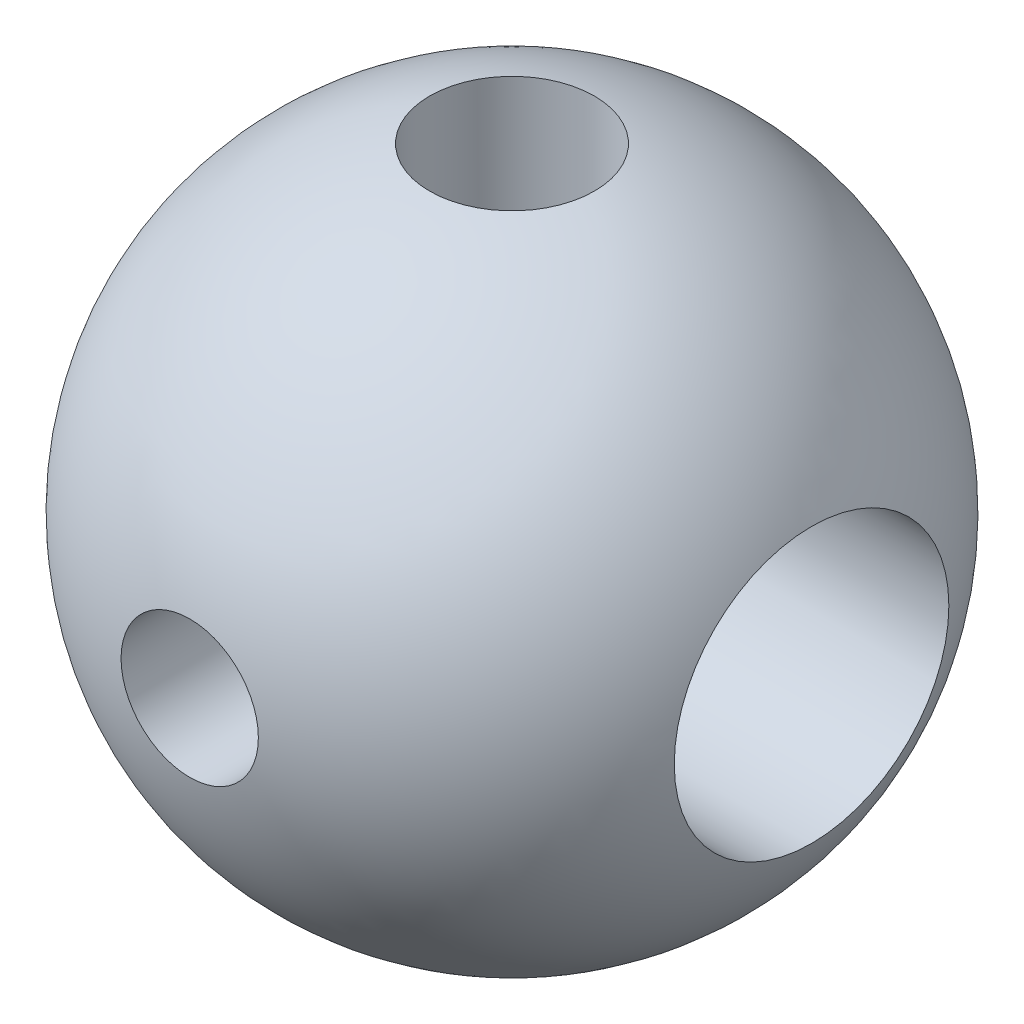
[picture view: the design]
ISO-10303-21;
HEADER;
FILE_DESCRIPTION(('STEP AP214'),'2;1');
FILE_NAME('part.step','',(''),(''),'','','');
FILE_SCHEMA(('AUTOMOTIVE_DESIGN { 1 0 10303 214 1 1 1 1 }'));
ENDSEC;
DATA;
#1=APPLICATION_CONTEXT('core data for automotive mechanical design processes');
#2=APPLICATION_PROTOCOL_DEFINITION('international standard','automotive_design',2000,#1);
#3=PRODUCT_CONTEXT('',#1,'mechanical');
#4=PRODUCT('Part','Part','',(#3));
#5=PRODUCT_RELATED_PRODUCT_CATEGORY('part','',(#4));
#6=PRODUCT_DEFINITION_FORMATION('','',#4);
#7=PRODUCT_DEFINITION_CONTEXT('part definition',#1,'design');
#8=PRODUCT_DEFINITION('design','',#6,#7);
#9=PRODUCT_DEFINITION_SHAPE('','',#8);
#10=(LENGTH_UNIT() NAMED_UNIT(*) SI_UNIT(.MILLI.,.METRE.));
#11=(NAMED_UNIT(*) PLANE_ANGLE_UNIT() SI_UNIT($,.RADIAN.));
#12=(NAMED_UNIT(*) SI_UNIT($,.STERADIAN.) SOLID_ANGLE_UNIT());
#13=UNCERTAINTY_MEASURE_WITH_UNIT(LENGTH_MEASURE(1.E-05),#10,'distance_accuracy_value','');
#14=(GEOMETRIC_REPRESENTATION_CONTEXT(3) GLOBAL_UNCERTAINTY_ASSIGNED_CONTEXT((#13)) GLOBAL_UNIT_ASSIGNED_CONTEXT((#10,
#11,#12)) REPRESENTATION_CONTEXT('',''));
#15=CARTESIAN_POINT('',(0.,0.,0.));
#16=DIRECTION('',(0.,0.,1.));
#17=DIRECTION('',(1.,0.,0.));
#18=AXIS2_PLACEMENT_3D('',#15,#16,#17);
#19=CARTESIAN_POINT('',(0.,-48.,0.));
#20=DIRECTION('',(0.,1.,0.));
#21=DIRECTION('',(0.,0.,1.));
#22=AXIS2_PLACEMENT_3D('',#19,#20,#21);
#23=CYLINDRICAL_SURFACE('',#22,12.);
#24=CARTESIAN_POINT('',(0.,-16.,12.));
#25=CARTESIAN_POINT('',(0.301908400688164,-15.9999971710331,12.0000019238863));
#26=CARTESIAN_POINT('',(0.603795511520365,-16.0085762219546,11.9885900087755));
#27=CARTESIAN_POINT('',(1.20488924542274,-16.0424977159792,11.9431600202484));
#28=CARTESIAN_POINT('',(1.50409604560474,-16.0678390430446,11.9091434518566));
#29=CARTESIAN_POINT('',(2.09765466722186,-16.1342200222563,11.8190547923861));
#30=CARTESIAN_POINT('',(2.39200179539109,-16.1752740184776,11.7629625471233));
#31=CARTESIAN_POINT('',(2.97349307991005,-16.2714289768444,11.6295889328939));
#32=CARTESIAN_POINT('',(3.26063685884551,-16.3265306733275,11.5523064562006));
#33=CARTESIAN_POINT('',(3.82391010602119,-16.4483194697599,11.3782233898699));
#34=CARTESIAN_POINT('',(4.10010631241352,-16.5149160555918,11.2815744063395));
#35=CARTESIAN_POINT('',(4.64262215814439,-16.6578936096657,11.069369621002));
#36=CARTESIAN_POINT('',(4.90893780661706,-16.7342784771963,10.9538062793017));
#37=CARTESIAN_POINT('',(5.43063769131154,-16.8946796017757,10.7047527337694));
#38=CARTESIAN_POINT('',(5.68602189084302,-16.9786958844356,10.5712624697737));
#39=CARTESIAN_POINT('',(6.18509809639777,-17.1522796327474,10.2872252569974));
#40=CARTESIAN_POINT('',(6.42879086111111,-17.2418467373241,10.1366794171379));
#41=CARTESIAN_POINT('',(6.93296744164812,-17.4357521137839,9.79983575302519));
#42=CARTESIAN_POINT('',(7.19185705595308,-17.5405567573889,9.61141728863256));
#43=CARTESIAN_POINT('',(7.6933159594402,-17.7520540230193,9.21493722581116));
#44=CARTESIAN_POINT('',(7.93588414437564,-17.8587467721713,9.00687430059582));
#45=CARTESIAN_POINT('',(8.40402030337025,-18.0716369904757,8.57173550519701));
#46=CARTESIAN_POINT('',(8.62957276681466,-18.1778339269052,8.34464267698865));
#47=CARTESIAN_POINT('',(9.06235556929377,-18.3872358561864,7.87249861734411));
#48=CARTESIAN_POINT('',(9.26959217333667,-18.4904418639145,7.62745357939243));
#49=CARTESIAN_POINT('',(9.68614025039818,-18.7025608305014,7.092648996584));
#50=CARTESIAN_POINT('',(9.89323949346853,-18.8108789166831,6.80092220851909));
#51=CARTESIAN_POINT('',(10.2818845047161,-19.0181526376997,6.19770739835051));
#52=CARTESIAN_POINT('',(10.4634279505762,-19.1171074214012,5.88621758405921));
#53=CARTESIAN_POINT('',(10.7988768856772,-19.3027521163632,5.24546661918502));
#54=CARTESIAN_POINT('',(10.9528016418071,-19.3894505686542,4.91621806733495));
#55=CARTESIAN_POINT('',(11.2311195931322,-19.5480167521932,4.242037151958));
#56=CARTESIAN_POINT('',(11.3555176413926,-19.6198869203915,3.89710737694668));
#57=CARTESIAN_POINT('',(11.5624812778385,-19.7404306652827,3.22795776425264));
#58=CARTESIAN_POINT('',(11.6479057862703,-19.7906632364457,2.9049021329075));
#59=CARTESIAN_POINT('',(11.7917710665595,-19.8756757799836,2.25082759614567));
#60=CARTESIAN_POINT('',(11.8502134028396,-19.9104566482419,1.91980915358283));
#61=CARTESIAN_POINT('',(11.9391406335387,-19.9635118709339,1.25298686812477));
#62=CARTESIAN_POINT('',(11.9696474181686,-19.9817991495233,0.91718698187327));
#63=CARTESIAN_POINT('',(12.0022585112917,-20.0013507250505,0.243729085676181));
#64=CARTESIAN_POINT('',(12.0043657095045,-20.0026167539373,-0.0939287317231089));
#65=CARTESIAN_POINT('',(11.9816620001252,-19.9890013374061,-0.725958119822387));
#66=CARTESIAN_POINT('',(11.9601608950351,-19.9761053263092,-1.02049867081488));
#67=CARTESIAN_POINT('',(11.8956497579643,-19.9375477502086,-1.60634317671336));
#68=CARTESIAN_POINT('',(11.8526419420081,-19.9118875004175,-1.89764746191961));
#69=CARTESIAN_POINT('',(11.7456574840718,-19.848390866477,-2.47502497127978));
#70=CARTESIAN_POINT('',(11.681680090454,-19.8105540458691,-2.76109800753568));
#71=CARTESIAN_POINT('',(11.5335067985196,-19.7235439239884,-3.32619184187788));
#72=CARTESIAN_POINT('',(11.449310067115,-19.6743701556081,-3.60521234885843));
#73=CARTESIAN_POINT('',(11.2610805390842,-19.5654290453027,-4.15611235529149));
#74=CARTESIAN_POINT('',(11.1569409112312,-19.5056047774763,-4.42794398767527));
#75=CARTESIAN_POINT('',(10.9300876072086,-19.3767412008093,-4.96158056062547));
#76=CARTESIAN_POINT('',(10.8073673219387,-19.307698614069,-5.22338189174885));
#77=CARTESIAN_POINT('',(10.5444249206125,-19.1617572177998,-5.73567682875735));
#78=CARTESIAN_POINT('',(10.4042061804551,-19.0848599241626,-5.98617260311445));
#79=CARTESIAN_POINT('',(10.1071922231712,-18.9245792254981,-6.47506872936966));
#80=CARTESIAN_POINT('',(9.9503910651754,-18.8411934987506,-6.71346470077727));
#81=CARTESIAN_POINT('',(9.60153051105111,-18.6591712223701,-7.2049947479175));
#82=CARTESIAN_POINT('',(9.40749645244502,-18.5599019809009,-7.45649461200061));
#83=CARTESIAN_POINT('',(9.00104402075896,-18.3572263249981,-7.94238968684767));
#84=CARTESIAN_POINT('',(8.788624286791,-18.253819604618,-8.17678362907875));
#85=CARTESIAN_POINT('',(8.34612135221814,-18.0449339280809,-8.62799224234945));
#86=CARTESIAN_POINT('',(8.11601317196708,-17.939452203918,-8.84478112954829));
#87=CARTESIAN_POINT('',(7.63939133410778,-17.7289199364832,-9.25956168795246));
#88=CARTESIAN_POINT('',(7.39288234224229,-17.6238692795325,-9.45755866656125));
#89=CARTESIAN_POINT('',(6.85463170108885,-17.404560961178,-9.85590025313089));
#90=CARTESIAN_POINT('',(6.56096287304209,-17.290652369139,-10.053842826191));
#91=CARTESIAN_POINT('',(5.95522167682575,-17.0700064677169,-10.4240751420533));
#92=CARTESIAN_POINT('',(5.64314629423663,-16.9632703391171,-10.5963606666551));
#93=CARTESIAN_POINT('',(5.00243922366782,-16.7610308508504,-10.913439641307));
#94=CARTESIAN_POINT('',(4.67383329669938,-16.6655107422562,-11.0582742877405));
#95=CARTESIAN_POINT('',(4.00145187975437,-16.4895880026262,-11.3189334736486));
#96=CARTESIAN_POINT('',(3.65768241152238,-16.409179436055,-11.4347694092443));
#97=CARTESIAN_POINT('',(3.04421360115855,-16.2849826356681,-11.610679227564));
#98=CARTESIAN_POINT('',(2.77725775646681,-16.2370569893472,-11.6774582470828));
#99=CARTESIAN_POINT('',(2.23756206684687,-16.1535036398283,-11.7927693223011));
#100=CARTESIAN_POINT('',(1.96482351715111,-16.117873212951,-11.8413054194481));
#101=CARTESIAN_POINT('',(1.41548658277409,-16.0601704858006,-11.9194501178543));
#102=CARTESIAN_POINT('',(1.13889216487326,-16.0380851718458,-11.9490768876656));
#103=CARTESIAN_POINT('',(0.583526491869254,-16.0082363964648,-11.9890365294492));
#104=CARTESIAN_POINT('',(0.304755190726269,-16.0004732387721,-11.9993689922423));
#105=CARTESIAN_POINT('',(-0.253237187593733,-15.9995682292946,-12.0005757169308));
#106=CARTESIAN_POINT('',(-0.532458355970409,-16.0064465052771,-11.9914231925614));
#107=CARTESIAN_POINT('',(-1.08885114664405,-16.0345997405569,-11.9537507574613));
#108=CARTESIAN_POINT('',(-1.36602275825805,-16.0558747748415,-11.9252307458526));
#109=CARTESIAN_POINT('',(-1.91652811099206,-16.1120462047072,-11.8492273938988));
#110=CARTESIAN_POINT('',(-2.18985914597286,-16.1469517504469,-11.8017313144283));
#111=CARTESIAN_POINT('',(-2.73078140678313,-16.229161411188,-11.6884218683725));
#112=CARTESIAN_POINT('',(-2.9983724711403,-16.2764658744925,-11.6226079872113));
#113=CARTESIAN_POINT('',(-3.52598231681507,-16.3818746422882,-11.4735560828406));
#114=CARTESIAN_POINT('',(-3.78601230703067,-16.4399619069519,-11.3903455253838));
#115=CARTESIAN_POINT('',(-4.29791560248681,-16.5653390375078,-11.2072231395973));
#116=CARTESIAN_POINT('',(-4.54978620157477,-16.6326319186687,-11.1073058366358));
#117=CARTESIAN_POINT('',(-5.04444759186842,-16.7746924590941,-10.8915731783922));
#118=CARTESIAN_POINT('',(-5.2872377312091,-16.8494606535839,-10.775756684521));
#119=CARTESIAN_POINT('',(-5.76305724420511,-17.0047712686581,-10.5289606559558));
#120=CARTESIAN_POINT('',(-5.99608608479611,-17.0853140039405,-10.3979802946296));
#121=CARTESIAN_POINT('',(-6.49298270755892,-17.2654555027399,-10.0965427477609));
#122=CARTESIAN_POINT('',(-6.75482499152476,-17.3658698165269,-9.92322733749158));
#123=CARTESIAN_POINT('',(-7.26327586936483,-17.5698876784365,-9.55734884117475));
#124=CARTESIAN_POINT('',(-7.50988693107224,-17.6734907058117,-9.36478888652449));
#125=CARTESIAN_POINT('',(-7.98738394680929,-17.8816130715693,-8.9610015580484));
#126=CARTESIAN_POINT('',(-8.21825388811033,-17.986133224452,-8.7497556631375));
#127=CARTESIAN_POINT('',(-8.66313204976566,-18.193711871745,-8.30951773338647));
#128=CARTESIAN_POINT('',(-8.8771393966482,-18.296770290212,-8.08052478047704));
#129=CARTESIAN_POINT('',(-9.31404007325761,-18.5124468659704,-7.57459119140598));
#130=CARTESIAN_POINT('',(-9.53446002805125,-18.6245617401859,-7.29529028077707));
#131=CARTESIAN_POINT('',(-9.95088052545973,-18.8411358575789,-6.71618728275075));
#132=CARTESIAN_POINT('',(-10.1468785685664,-18.9455943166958,-6.41638310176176));
#133=CARTESIAN_POINT('',(-10.512504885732,-19.1439071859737,-5.79794763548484));
#134=CARTESIAN_POINT('',(-10.6821457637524,-19.2377666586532,-5.47932545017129));
#135=CARTESIAN_POINT('',(-10.993163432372,-19.4121884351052,-4.82508968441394));
#136=CARTESIAN_POINT('',(-11.1345440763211,-19.4927525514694,-4.48947842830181));
#137=CARTESIAN_POINT('',(-11.3778836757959,-19.6328061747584,-3.82865235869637));
#138=CARTESIAN_POINT('',(-11.4819596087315,-19.6934011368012,-3.50445198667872));
#139=CARTESIAN_POINT('',(-11.6626203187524,-19.7992764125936,-2.84601413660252));
#140=CARTESIAN_POINT('',(-11.7392061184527,-19.8445572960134,-2.51177703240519));
#141=CARTESIAN_POINT('',(-11.8636029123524,-19.9183977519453,-1.83648767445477));
#142=CARTESIAN_POINT('',(-11.911441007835,-19.946973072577,-1.49544215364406));
#143=CARTESIAN_POINT('',(-11.9776197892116,-19.9865620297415,-0.809503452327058));
#144=CARTESIAN_POINT('',(-11.9959643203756,-19.9975779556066,-0.464610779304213));
#145=CARTESIAN_POINT('',(-12.0023854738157,-20.001431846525,0.179455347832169));
#146=CARTESIAN_POINT('',(-11.9941753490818,-19.9964998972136,0.478586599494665));
#147=CARTESIAN_POINT('',(-11.95549677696,-19.9733236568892,1.07486280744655));
#148=CARTESIAN_POINT('',(-11.9250307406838,-19.9550808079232,1.37200797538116));
#149=CARTESIAN_POINT('',(-11.8422465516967,-19.9057203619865,1.96213810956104));
#150=CARTESIAN_POINT('',(-11.7899285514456,-19.8746028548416,2.25512310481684));
#151=CARTESIAN_POINT('',(-11.6640981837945,-19.8002174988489,2.83492894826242));
#152=CARTESIAN_POINT('',(-11.5905851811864,-19.756949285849,3.12174961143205));
#153=CARTESIAN_POINT('',(-11.4245704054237,-19.660018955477,3.68285438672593));
#154=CARTESIAN_POINT('',(-11.3323940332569,-19.6065357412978,3.95726608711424));
#155=CARTESIAN_POINT('',(-11.1292862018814,-19.4898461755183,4.4968998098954));
#156=CARTESIAN_POINT('',(-11.0183552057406,-19.4266400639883,4.76212205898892));
#157=CARTESIAN_POINT('',(-10.7787258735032,-19.291737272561,5.2821427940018));
#158=CARTESIAN_POINT('',(-10.6500282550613,-19.2200409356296,5.53694170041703));
#159=CARTESIAN_POINT('',(-10.3758015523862,-19.0694552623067,6.03520075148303));
#160=CARTESIAN_POINT('',(-10.2302663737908,-18.9905633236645,6.27865674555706));
#161=CARTESIAN_POINT('',(-9.90673029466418,-18.8181451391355,6.77899616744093));
#162=CARTESIAN_POINT('',(-9.72692044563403,-18.7239589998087,7.03448334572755));
#163=CARTESIAN_POINT('',(-9.348935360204,-18.5304135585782,7.52957259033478));
#164=CARTESIAN_POINT('',(-9.15075189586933,-18.4310519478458,7.76916745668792));
#165=CARTESIAN_POINT('',(-8.7369667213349,-18.2291509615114,8.23175510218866));
#166=CARTESIAN_POINT('',(-8.52135096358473,-18.1266090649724,8.45473420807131));
#167=CARTESIAN_POINT('',(-8.07376590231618,-17.9205531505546,8.88314617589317));
#168=CARTESIAN_POINT('',(-7.84179571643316,-17.8170390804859,9.08857808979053));
#169=CARTESIAN_POINT('',(-7.33186369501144,-17.5982003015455,9.50608800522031));
#170=CARTESIAN_POINT('',(-7.05180187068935,-17.4830446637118,9.71569839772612));
#171=CARTESIAN_POINT('',(-6.47302014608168,-17.2577211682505,10.110526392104));
#172=CARTESIAN_POINT('',(-6.17429798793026,-17.1475539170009,10.2957410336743));
#173=CARTESIAN_POINT('',(-5.55945257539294,-16.9358863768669,10.6403306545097));
#174=CARTESIAN_POINT('',(-5.24333396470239,-16.8343837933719,10.7997124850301));
#175=CARTESIAN_POINT('',(-4.59511438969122,-16.6438937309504,11.0910374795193));
#176=CARTESIAN_POINT('',(-4.26301779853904,-16.5549028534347,11.2229880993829));
#177=CARTESIAN_POINT('',(-3.61366723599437,-16.4002389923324,11.4476706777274));
#178=CARTESIAN_POINT('',(-3.29755988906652,-16.3332252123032,11.5427864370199));
#179=CARTESIAN_POINT('',(-2.6556392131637,-16.2158236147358,11.7071473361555));
#180=CARTESIAN_POINT('',(-2.32982667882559,-16.1654344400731,11.7763945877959));
#181=CARTESIAN_POINT('',(-1.67181932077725,-16.0838007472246,11.8876462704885));
#182=CARTESIAN_POINT('',(-1.33963755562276,-16.0525206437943,11.929701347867));
#183=CARTESIAN_POINT('',(-0.671628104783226,-16.0106231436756,11.9858753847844));
#184=CARTESIAN_POINT('',(-0.335800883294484,-16.000003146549,11.9999978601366));
#185=CARTESIAN_POINT('',(0.,-16.,12.));
#186=B_SPLINE_CURVE_WITH_KNOTS('',3,(#24,#25,#26,#27,#28,#29,#30,#31,#32,#33,#34,#35,#36,#37,
#38,#39,#40,#41,#42,#43,#44,#45,#46,#47,#48,#49,#50,#51,#52,#53,#54,#55,#56,#57,#58,#59,#60,#61,
#62,#63,#64,#65,#66,#67,#68,#69,#70,#71,#72,#73,#74,#75,#76,#77,#78,#79,#80,#81,#82,#83,#84,#85,
#86,#87,#88,#89,#90,#91,#92,#93,#94,#95,#96,#97,#98,#99,#100,#101,#102,#103,#104,#105,#106,#107,
#108,#109,#110,#111,#112,#113,#114,#115,#116,#117,#118,#119,#120,#121,#122,#123,#124,#125,#126,
#127,#128,#129,#130,#131,#132,#133,#134,#135,#136,#137,#138,#139,#140,#141,#142,#143,#144,#145,
#146,#147,#148,#149,#150,#151,#152,#153,#154,#155,#156,#157,#158,#159,#160,#161,#162,#163,#164,
#165,#166,#167,#168,#169,#170,#171,#172,#173,#174,#175,#176,#177,#178,#179,#180,#181,#182,#183,
#184,#185),.UNSPECIFIED.,.T.,.F.,(4,2,2,2,2,2,2,2,2,2,2,2,2,2,2,2,2,2,2,2,2,2,2,2,2,2,2,2,2,2,2,
2,2,2,2,2,2,2,2,2,2,2,2,2,2,2,2,2,2,2,2,2,2,2,2,2,2,2,2,2,2,2,2,2,2,2,2,2,2,2,2,2,2,2,2,2,2,2,2,
2,4),(0.,0.905356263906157,1.81065225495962,2.71677666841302,3.62294845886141,4.5222857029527,
5.42198232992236,6.32168197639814,7.22132315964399,8.23104850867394,9.24084210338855,
10.2515453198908,11.2619014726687,12.3818273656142,13.5018549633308,14.6210981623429,
15.7401572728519,16.7524414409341,17.7646669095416,18.7760985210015,19.7874272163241,
20.673184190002,21.5588499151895,22.4445473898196,23.3302813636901,24.2208999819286,
25.1118361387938,26.0026006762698,26.8936854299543,27.8910660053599,28.8885204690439,
29.8874103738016,30.8860173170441,32.0006941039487,33.1155539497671,34.2287272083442,
35.3414623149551,36.1785892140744,37.0155305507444,37.8516665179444,38.6878202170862,
39.5251241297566,40.3624324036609,41.2003037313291,42.0381985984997,42.8747804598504,
43.7116369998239,44.5485535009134,45.3855156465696,46.3735461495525,47.3614161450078,
48.3502765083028,49.3391880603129,50.456908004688,51.5747422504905,52.6920402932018,
53.8091858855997,54.8452180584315,55.881211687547,56.9162271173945,57.9511075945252,
58.8478548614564,59.7445049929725,60.6411488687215,61.5378196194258,62.4200276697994,
63.3022139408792,64.1843645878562,65.0668355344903,66.044765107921,67.0231347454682,
68.002300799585,68.9815197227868,70.0850618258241,71.1887377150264,72.2921204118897,
73.3952028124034,74.4042890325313,75.413292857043,76.4204119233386,77.427404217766),.UNSPECIFIED.);
#187=CARTESIAN_POINT('',(0.,-16.,12.));
#188=VERTEX_POINT('',#187);
#189=EDGE_CURVE('E62',#188,#188,#186,.T.);
#190=ORIENTED_EDGE('',*,*,#189,.T.);
#191=EDGE_LOOP('',(#190));
#192=FACE_BOUND('',#191,.T.);
#193=CARTESIAN_POINT('',(0.,-46.475800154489,0.));
#194=DIRECTION('',(0.,1.,0.));
#195=DIRECTION('',(0.,0.,1.));
#196=AXIS2_PLACEMENT_3D('',#193,#194,#195);
#197=CIRCLE('',#196,12.);
#198=CARTESIAN_POINT('',(0.,-46.475800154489,12.));
#199=VERTEX_POINT('',#198);
#200=EDGE_CURVE('E48',#199,#199,#197,.F.);
#201=ORIENTED_EDGE('',*,*,#200,.T.);
#202=EDGE_LOOP('',(#201));
#203=FACE_BOUND('',#202,.T.);
#204=ADVANCED_FACE('F36',(#192,#203),#23,.F.);
#205=CARTESIAN_POINT('',(0.,0.,0.));
#206=DIRECTION('',(0.,1.,0.));
#207=DIRECTION('',(1.,0.,0.));
#208=AXIS2_PLACEMENT_3D('',#205,#206,#207);
#209=SPHERICAL_SURFACE('',#208,48.);
#210=CARTESIAN_POINT('',(0.,0.,46.946778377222));
#211=DIRECTION('',(0.,0.,-1.));
#212=DIRECTION('',(-1.,0.,0.));
#213=AXIS2_PLACEMENT_3D('',#210,#211,#212);
#214=CIRCLE('',#213,10.);
#215=CARTESIAN_POINT('',(-10.,0.,46.946778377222));
#216=VERTEX_POINT('',#215);
#217=EDGE_CURVE('E63',#216,#216,#214,.F.);
#218=ORIENTED_EDGE('',*,*,#217,.F.);
#219=EDGE_LOOP('',(#218));
#220=FACE_BOUND('',#219,.T.);
#221=CARTESIAN_POINT('',(0.,0.,-46.946778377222));
#222=DIRECTION('',(0.,0.,1.));
#223=DIRECTION('',(1.,0.,0.));
#224=AXIS2_PLACEMENT_3D('',#221,#222,#223);
#225=CIRCLE('',#224,10.);
#226=CARTESIAN_POINT('',(10.,0.,-46.946778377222));
#227=VERTEX_POINT('',#226);
#228=EDGE_CURVE('E85',#227,#227,#225,.F.);
#229=ORIENTED_EDGE('',*,*,#228,.F.);
#230=EDGE_LOOP('',(#229));
#231=FACE_BOUND('',#230,.T.);
#232=CARTESIAN_POINT('',(43.6348484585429,0.,0.));
#233=DIRECTION('',(-1.,0.,0.));
#234=DIRECTION('',(0.,0.,1.));
#235=AXIS2_PLACEMENT_3D('',#232,#233,#234);
#236=CIRCLE('',#235,20.);
#237=CARTESIAN_POINT('',(43.6348484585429,0.,20.));
#238=VERTEX_POINT('',#237);
#239=EDGE_CURVE('E53',#238,#238,#236,.F.);
#240=ORIENTED_EDGE('',*,*,#239,.F.);
#241=EDGE_LOOP('',(#240));
#242=FACE_BOUND('',#241,.T.);
#243=CARTESIAN_POINT('',(-43.6348484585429,0.,0.));
#244=DIRECTION('',(1.,0.,0.));
#245=DIRECTION('',(0.,0.,-1.));
#246=AXIS2_PLACEMENT_3D('',#243,#244,#245);
#247=CIRCLE('',#246,20.);
#248=CARTESIAN_POINT('',(-43.6348484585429,0.,-20.));
#249=VERTEX_POINT('',#248);
#250=EDGE_CURVE('E94',#249,#249,#247,.F.);
#251=ORIENTED_EDGE('',*,*,#250,.F.);
#252=EDGE_LOOP('',(#251));
#253=FACE_BOUND('',#252,.T.);
#254=CARTESIAN_POINT('',(0.,46.475800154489,0.));
#255=DIRECTION('',(0.,-1.,0.));
#256=DIRECTION('',(0.,0.,-1.));
#257=AXIS2_PLACEMENT_3D('',#254,#255,#256);
#258=CIRCLE('',#257,12.);
#259=CARTESIAN_POINT('',(0.,46.475800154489,-12.));
#260=VERTEX_POINT('',#259);
#261=EDGE_CURVE('E10',#260,#260,#258,.F.);
#262=ORIENTED_EDGE('',*,*,#261,.F.);
#263=EDGE_LOOP('',(#262));
#264=FACE_BOUND('',#263,.T.);
#265=ORIENTED_EDGE('',*,*,#200,.F.);
#266=EDGE_LOOP('',(#265));
#267=FACE_BOUND('',#266,.T.);
#268=ADVANCED_FACE('F38',(#220,#231,#242,#253,#264,#267),#209,.T.);
#269=CARTESIAN_POINT('',(0.,16.,12.));
#270=CARTESIAN_POINT('',(-0.301908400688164,15.9999971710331,12.0000019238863));
#271=CARTESIAN_POINT('',(-0.603795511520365,16.0085762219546,11.9885900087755));
#272=CARTESIAN_POINT('',(-1.20488924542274,16.0424977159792,11.9431600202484));
#273=CARTESIAN_POINT('',(-1.50409604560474,16.0678390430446,11.9091434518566));
#274=CARTESIAN_POINT('',(-2.09765466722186,16.1342200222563,11.8190547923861));
#275=CARTESIAN_POINT('',(-2.39200179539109,16.1752740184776,11.7629625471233));
#276=CARTESIAN_POINT('',(-2.97349307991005,16.2714289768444,11.6295889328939));
#277=CARTESIAN_POINT('',(-3.26063685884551,16.3265306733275,11.5523064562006));
#278=CARTESIAN_POINT('',(-3.82391010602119,16.4483194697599,11.3782233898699));
#279=CARTESIAN_POINT('',(-4.10010631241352,16.5149160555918,11.2815744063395));
#280=CARTESIAN_POINT('',(-4.64262215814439,16.6578936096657,11.069369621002));
#281=CARTESIAN_POINT('',(-4.90893780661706,16.7342784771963,10.9538062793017));
#282=CARTESIAN_POINT('',(-5.43063769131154,16.8946796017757,10.7047527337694));
#283=CARTESIAN_POINT('',(-5.68602189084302,16.9786958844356,10.5712624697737));
#284=CARTESIAN_POINT('',(-6.18509809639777,17.1522796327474,10.2872252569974));
#285=CARTESIAN_POINT('',(-6.42879086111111,17.2418467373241,10.1366794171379));
#286=CARTESIAN_POINT('',(-6.93296744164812,17.4357521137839,9.79983575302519));
#287=CARTESIAN_POINT('',(-7.19185705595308,17.5405567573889,9.61141728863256));
#288=CARTESIAN_POINT('',(-7.6933159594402,17.7520540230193,9.21493722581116));
#289=CARTESIAN_POINT('',(-7.93588414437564,17.8587467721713,9.00687430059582));
#290=CARTESIAN_POINT('',(-8.40402030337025,18.0716369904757,8.57173550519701));
#291=CARTESIAN_POINT('',(-8.62957276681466,18.1778339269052,8.34464267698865));
#292=CARTESIAN_POINT('',(-9.06235556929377,18.3872358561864,7.87249861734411));
#293=CARTESIAN_POINT('',(-9.26959217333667,18.4904418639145,7.62745357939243));
#294=CARTESIAN_POINT('',(-9.68614025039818,18.7025608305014,7.092648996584));
#295=CARTESIAN_POINT('',(-9.89323949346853,18.8108789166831,6.80092220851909));
#296=CARTESIAN_POINT('',(-10.2818845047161,19.0181526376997,6.19770739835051));
#297=CARTESIAN_POINT('',(-10.4634279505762,19.1171074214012,5.88621758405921));
#298=CARTESIAN_POINT('',(-10.7988768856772,19.3027521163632,5.24546661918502));
#299=CARTESIAN_POINT('',(-10.9528016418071,19.3894505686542,4.91621806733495));
#300=CARTESIAN_POINT('',(-11.2311195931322,19.5480167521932,4.242037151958));
#301=CARTESIAN_POINT('',(-11.3555176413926,19.6198869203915,3.89710737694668));
#302=CARTESIAN_POINT('',(-11.5624812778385,19.7404306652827,3.22795776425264));
#303=CARTESIAN_POINT('',(-11.6479057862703,19.7906632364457,2.9049021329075));
#304=CARTESIAN_POINT('',(-11.7917710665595,19.8756757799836,2.25082759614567));
#305=CARTESIAN_POINT('',(-11.8502134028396,19.9104566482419,1.91980915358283));
#306=CARTESIAN_POINT('',(-11.9391406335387,19.9635118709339,1.25298686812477));
#307=CARTESIAN_POINT('',(-11.9696474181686,19.9817991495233,0.91718698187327));
#308=CARTESIAN_POINT('',(-12.0022585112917,20.0013507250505,0.243729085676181));
#309=CARTESIAN_POINT('',(-12.0043657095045,20.0026167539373,-0.0939287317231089));
#310=CARTESIAN_POINT('',(-11.9816620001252,19.9890013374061,-0.725958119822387));
#311=CARTESIAN_POINT('',(-11.9601608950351,19.9761053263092,-1.02049867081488));
#312=CARTESIAN_POINT('',(-11.8956497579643,19.9375477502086,-1.60634317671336));
#313=CARTESIAN_POINT('',(-11.8526419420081,19.9118875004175,-1.89764746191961));
#314=CARTESIAN_POINT('',(-11.7456574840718,19.848390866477,-2.47502497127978));
#315=CARTESIAN_POINT('',(-11.681680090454,19.8105540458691,-2.76109800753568));
#316=CARTESIAN_POINT('',(-11.5335067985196,19.7235439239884,-3.32619184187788));
#317=CARTESIAN_POINT('',(-11.449310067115,19.6743701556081,-3.60521234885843));
#318=CARTESIAN_POINT('',(-11.2610805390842,19.5654290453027,-4.15611235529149));
#319=CARTESIAN_POINT('',(-11.1569409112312,19.5056047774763,-4.42794398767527));
#320=CARTESIAN_POINT('',(-10.9300876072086,19.3767412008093,-4.96158056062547));
#321=CARTESIAN_POINT('',(-10.8073673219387,19.307698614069,-5.22338189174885));
#322=CARTESIAN_POINT('',(-10.5444249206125,19.1617572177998,-5.73567682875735));
#323=CARTESIAN_POINT('',(-10.4042061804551,19.0848599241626,-5.98617260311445));
#324=CARTESIAN_POINT('',(-10.1071922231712,18.9245792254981,-6.47506872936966));
#325=CARTESIAN_POINT('',(-9.9503910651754,18.8411934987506,-6.71346470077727));
#326=CARTESIAN_POINT('',(-9.60153051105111,18.6591712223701,-7.2049947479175));
#327=CARTESIAN_POINT('',(-9.40749645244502,18.5599019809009,-7.45649461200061));
#328=CARTESIAN_POINT('',(-9.00104402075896,18.3572263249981,-7.94238968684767));
#329=CARTESIAN_POINT('',(-8.788624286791,18.253819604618,-8.17678362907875));
#330=CARTESIAN_POINT('',(-8.34612135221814,18.0449339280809,-8.62799224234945));
#331=CARTESIAN_POINT('',(-8.11601317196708,17.939452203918,-8.84478112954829));
#332=CARTESIAN_POINT('',(-7.63939133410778,17.7289199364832,-9.25956168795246));
#333=CARTESIAN_POINT('',(-7.39288234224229,17.6238692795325,-9.45755866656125));
#334=CARTESIAN_POINT('',(-6.85463170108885,17.404560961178,-9.85590025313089));
#335=CARTESIAN_POINT('',(-6.56096287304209,17.290652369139,-10.053842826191));
#336=CARTESIAN_POINT('',(-5.95522167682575,17.0700064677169,-10.4240751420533));
#337=CARTESIAN_POINT('',(-5.64314629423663,16.9632703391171,-10.5963606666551));
#338=CARTESIAN_POINT('',(-5.00243922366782,16.7610308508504,-10.913439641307));
#339=CARTESIAN_POINT('',(-4.67383329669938,16.6655107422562,-11.0582742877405));
#340=CARTESIAN_POINT('',(-4.00145187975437,16.4895880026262,-11.3189334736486));
#341=CARTESIAN_POINT('',(-3.65768241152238,16.409179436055,-11.4347694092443));
#342=CARTESIAN_POINT('',(-3.04421360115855,16.2849826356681,-11.610679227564));
#343=CARTESIAN_POINT('',(-2.77725775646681,16.2370569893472,-11.6774582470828));
#344=CARTESIAN_POINT('',(-2.23756206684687,16.1535036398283,-11.7927693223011));
#345=CARTESIAN_POINT('',(-1.96482351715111,16.117873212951,-11.8413054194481));
#346=CARTESIAN_POINT('',(-1.41548658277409,16.0601704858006,-11.9194501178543));
#347=CARTESIAN_POINT('',(-1.13889216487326,16.0380851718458,-11.9490768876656));
#348=CARTESIAN_POINT('',(-0.583526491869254,16.0082363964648,-11.9890365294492));
#349=CARTESIAN_POINT('',(-0.304755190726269,16.0004732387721,-11.9993689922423));
#350=CARTESIAN_POINT('',(0.253237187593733,15.9995682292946,-12.0005757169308));
#351=CARTESIAN_POINT('',(0.532458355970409,16.0064465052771,-11.9914231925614));
#352=CARTESIAN_POINT('',(1.08885114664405,16.0345997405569,-11.9537507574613));
#353=CARTESIAN_POINT('',(1.36602275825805,16.0558747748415,-11.9252307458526));
#354=CARTESIAN_POINT('',(1.91652811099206,16.1120462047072,-11.8492273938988));
#355=CARTESIAN_POINT('',(2.18985914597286,16.1469517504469,-11.8017313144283));
#356=CARTESIAN_POINT('',(2.73078140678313,16.229161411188,-11.6884218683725));
#357=CARTESIAN_POINT('',(2.9983724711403,16.2764658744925,-11.6226079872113));
#358=CARTESIAN_POINT('',(3.52598231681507,16.3818746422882,-11.4735560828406));
#359=CARTESIAN_POINT('',(3.78601230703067,16.4399619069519,-11.3903455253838));
#360=CARTESIAN_POINT('',(4.29791560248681,16.5653390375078,-11.2072231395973));
#361=CARTESIAN_POINT('',(4.54978620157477,16.6326319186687,-11.1073058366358));
#362=CARTESIAN_POINT('',(5.04444759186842,16.7746924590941,-10.8915731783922));
#363=CARTESIAN_POINT('',(5.2872377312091,16.8494606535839,-10.775756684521));
#364=CARTESIAN_POINT('',(5.76305724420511,17.0047712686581,-10.5289606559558));
#365=CARTESIAN_POINT('',(5.99608608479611,17.0853140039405,-10.3979802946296));
#366=CARTESIAN_POINT('',(6.49298270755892,17.2654555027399,-10.0965427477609));
#367=CARTESIAN_POINT('',(6.75482499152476,17.3658698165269,-9.92322733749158));
#368=CARTESIAN_POINT('',(7.26327586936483,17.5698876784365,-9.55734884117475));
#369=CARTESIAN_POINT('',(7.50988693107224,17.6734907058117,-9.36478888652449));
#370=CARTESIAN_POINT('',(7.98738394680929,17.8816130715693,-8.9610015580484));
#371=CARTESIAN_POINT('',(8.21825388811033,17.986133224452,-8.7497556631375));
#372=CARTESIAN_POINT('',(8.66313204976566,18.193711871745,-8.30951773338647));
#373=CARTESIAN_POINT('',(8.8771393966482,18.296770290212,-8.08052478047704));
#374=CARTESIAN_POINT('',(9.31404007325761,18.5124468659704,-7.57459119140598));
#375=CARTESIAN_POINT('',(9.53446002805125,18.6245617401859,-7.29529028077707));
#376=CARTESIAN_POINT('',(9.95088052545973,18.8411358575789,-6.71618728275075));
#377=CARTESIAN_POINT('',(10.1468785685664,18.9455943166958,-6.41638310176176));
#378=CARTESIAN_POINT('',(10.512504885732,19.1439071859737,-5.79794763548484));
#379=CARTESIAN_POINT('',(10.6821457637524,19.2377666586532,-5.47932545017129));
#380=CARTESIAN_POINT('',(10.993163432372,19.4121884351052,-4.82508968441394));
#381=CARTESIAN_POINT('',(11.1345440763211,19.4927525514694,-4.48947842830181));
#382=CARTESIAN_POINT('',(11.3778836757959,19.6328061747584,-3.82865235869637));
#383=CARTESIAN_POINT('',(11.4819596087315,19.6934011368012,-3.50445198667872));
#384=CARTESIAN_POINT('',(11.6626203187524,19.7992764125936,-2.84601413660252));
#385=CARTESIAN_POINT('',(11.7392061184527,19.8445572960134,-2.51177703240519));
#386=CARTESIAN_POINT('',(11.8636029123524,19.9183977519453,-1.83648767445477));
#387=CARTESIAN_POINT('',(11.911441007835,19.946973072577,-1.49544215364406));
#388=CARTESIAN_POINT('',(11.9776197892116,19.9865620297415,-0.809503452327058));
#389=CARTESIAN_POINT('',(11.9959643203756,19.9975779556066,-0.464610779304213));
#390=CARTESIAN_POINT('',(12.0023854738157,20.001431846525,0.179455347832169));
#391=CARTESIAN_POINT('',(11.9941753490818,19.9964998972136,0.478586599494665));
#392=CARTESIAN_POINT('',(11.95549677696,19.9733236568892,1.07486280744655));
#393=CARTESIAN_POINT('',(11.9250307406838,19.9550808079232,1.37200797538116));
#394=CARTESIAN_POINT('',(11.8422465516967,19.9057203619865,1.96213810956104));
#395=CARTESIAN_POINT('',(11.7899285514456,19.8746028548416,2.25512310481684));
#396=CARTESIAN_POINT('',(11.6640981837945,19.8002174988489,2.83492894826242));
#397=CARTESIAN_POINT('',(11.5905851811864,19.756949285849,3.12174961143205));
#398=CARTESIAN_POINT('',(11.4245704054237,19.660018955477,3.68285438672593));
#399=CARTESIAN_POINT('',(11.3323940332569,19.6065357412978,3.95726608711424));
#400=CARTESIAN_POINT('',(11.1292862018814,19.4898461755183,4.4968998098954));
#401=CARTESIAN_POINT('',(11.0183552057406,19.4266400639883,4.76212205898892));
#402=CARTESIAN_POINT('',(10.7787258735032,19.291737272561,5.2821427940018));
#403=CARTESIAN_POINT('',(10.6500282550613,19.2200409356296,5.53694170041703));
#404=CARTESIAN_POINT('',(10.3758015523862,19.0694552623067,6.03520075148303));
#405=CARTESIAN_POINT('',(10.2302663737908,18.9905633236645,6.27865674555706));
#406=CARTESIAN_POINT('',(9.90673029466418,18.8181451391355,6.77899616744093));
#407=CARTESIAN_POINT('',(9.72692044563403,18.7239589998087,7.03448334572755));
#408=CARTESIAN_POINT('',(9.348935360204,18.5304135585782,7.52957259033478));
#409=CARTESIAN_POINT('',(9.15075189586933,18.4310519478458,7.76916745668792));
#410=CARTESIAN_POINT('',(8.7369667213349,18.2291509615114,8.23175510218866));
#411=CARTESIAN_POINT('',(8.52135096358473,18.1266090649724,8.45473420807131));
#412=CARTESIAN_POINT('',(8.07376590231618,17.9205531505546,8.88314617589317));
#413=CARTESIAN_POINT('',(7.84179571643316,17.8170390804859,9.08857808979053));
#414=CARTESIAN_POINT('',(7.33186369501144,17.5982003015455,9.50608800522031));
#415=CARTESIAN_POINT('',(7.05180187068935,17.4830446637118,9.71569839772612));
#416=CARTESIAN_POINT('',(6.47302014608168,17.2577211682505,10.110526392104));
#417=CARTESIAN_POINT('',(6.17429798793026,17.1475539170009,10.2957410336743));
#418=CARTESIAN_POINT('',(5.55945257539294,16.9358863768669,10.6403306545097));
#419=CARTESIAN_POINT('',(5.24333396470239,16.8343837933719,10.7997124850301));
#420=CARTESIAN_POINT('',(4.59511438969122,16.6438937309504,11.0910374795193));
#421=CARTESIAN_POINT('',(4.26301779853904,16.5549028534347,11.2229880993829));
#422=CARTESIAN_POINT('',(3.61366723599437,16.4002389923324,11.4476706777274));
#423=CARTESIAN_POINT('',(3.29755988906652,16.3332252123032,11.5427864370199));
#424=CARTESIAN_POINT('',(2.6556392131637,16.2158236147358,11.7071473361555));
#425=CARTESIAN_POINT('',(2.32982667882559,16.1654344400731,11.7763945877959));
#426=CARTESIAN_POINT('',(1.67181932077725,16.0838007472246,11.8876462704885));
#427=CARTESIAN_POINT('',(1.33963755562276,16.0525206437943,11.929701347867));
#428=CARTESIAN_POINT('',(0.671628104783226,16.0106231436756,11.9858753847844));
#429=CARTESIAN_POINT('',(0.335800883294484,16.000003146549,11.9999978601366));
#430=CARTESIAN_POINT('',(0.,16.,12.));
#431=B_SPLINE_CURVE_WITH_KNOTS('',3,(#269,#270,#271,#272,#273,#274,#275,#276,#277,#278,#279,
#280,#281,#282,#283,#284,#285,#286,#287,#288,#289,#290,#291,#292,#293,#294,#295,#296,#297,#298,
#299,#300,#301,#302,#303,#304,#305,#306,#307,#308,#309,#310,#311,#312,#313,#314,#315,#316,#317,
#318,#319,#320,#321,#322,#323,#324,#325,#326,#327,#328,#329,#330,#331,#332,#333,#334,#335,#336,
#337,#338,#339,#340,#341,#342,#343,#344,#345,#346,#347,#348,#349,#350,#351,#352,#353,#354,#355,
#356,#357,#358,#359,#360,#361,#362,#363,#364,#365,#366,#367,#368,#369,#370,#371,#372,#373,#374,
#375,#376,#377,#378,#379,#380,#381,#382,#383,#384,#385,#386,#387,#388,#389,#390,#391,#392,#393,
#394,#395,#396,#397,#398,#399,#400,#401,#402,#403,#404,#405,#406,#407,#408,#409,#410,#411,#412,
#413,#414,#415,#416,#417,#418,#419,#420,#421,#422,#423,#424,#425,#426,#427,#428,#429,#430),
.UNSPECIFIED.,.T.,.F.,(4,2,2,2,2,2,2,2,2,2,2,2,2,2,2,2,2,2,2,2,2,2,2,2,2,2,2,2,2,2,2,2,2,2,2,2,
2,2,2,2,2,2,2,2,2,2,2,2,2,2,2,2,2,2,2,2,2,2,2,2,2,2,2,2,2,2,2,2,2,2,2,2,2,2,2,2,2,2,2,2,4),(0.,
0.905356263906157,1.81065225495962,2.71677666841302,3.62294845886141,4.5222857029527,
5.42198232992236,6.32168197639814,7.22132315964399,8.23104850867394,9.24084210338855,
10.2515453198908,11.2619014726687,12.3818273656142,13.5018549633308,14.6210981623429,
15.7401572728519,16.7524414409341,17.7646669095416,18.7760985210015,19.7874272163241,
20.673184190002,21.5588499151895,22.4445473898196,23.3302813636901,24.2208999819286,
25.1118361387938,26.0026006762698,26.8936854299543,27.8910660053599,28.8885204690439,
29.8874103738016,30.8860173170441,32.0006941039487,33.1155539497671,34.2287272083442,
35.3414623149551,36.1785892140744,37.0155305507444,37.8516665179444,38.6878202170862,
39.5251241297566,40.3624324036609,41.2003037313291,42.0381985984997,42.8747804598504,
43.7116369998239,44.5485535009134,45.3855156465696,46.3735461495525,47.3614161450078,
48.3502765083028,49.3391880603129,50.456908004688,51.5747422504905,52.6920402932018,
53.8091858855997,54.8452180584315,55.881211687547,56.9162271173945,57.9511075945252,
58.8478548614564,59.7445049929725,60.6411488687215,61.5378196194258,62.4200276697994,
63.3022139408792,64.1843645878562,65.0668355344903,66.044765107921,67.0231347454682,
68.002300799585,68.9815197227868,70.0850618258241,71.1887377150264,72.2921204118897,
73.3952028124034,74.4042890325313,75.413292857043,76.4204119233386,77.427404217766),.UNSPECIFIED.);
#432=CARTESIAN_POINT('',(0.,16.,12.));
#433=VERTEX_POINT('',#432);
#434=EDGE_CURVE('E57',#433,#433,#431,.T.);
#435=ORIENTED_EDGE('',*,*,#434,.T.);
#436=EDGE_LOOP('',(#435));
#437=FACE_BOUND('',#436,.T.);
#438=ORIENTED_EDGE('',*,*,#261,.T.);
#439=EDGE_LOOP('',(#438));
#440=FACE_BOUND('',#439,.T.);
#441=ADVANCED_FACE('F66',(#437,#440),#23,.F.);
#442=CARTESIAN_POINT('',(-48.,0.,0.));
#443=DIRECTION('',(1.,0.,0.));
#444=DIRECTION('',(0.,0.,-1.));
#445=AXIS2_PLACEMENT_3D('',#442,#443,#444);
#446=CYLINDRICAL_SURFACE('',#445,20.);
#447=CARTESIAN_POINT('',(-10.,0.,-20.));
#448=CARTESIAN_POINT('',(-9.99999913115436,0.26297774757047,-19.9999992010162));
#449=CARTESIAN_POINT('',(-9.98961448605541,0.525973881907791,-19.9948010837));
#450=CARTESIAN_POINT('',(-9.94819417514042,1.05002923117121,-19.9741395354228));
#451=CARTESIAN_POINT('',(-9.91714952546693,1.31108755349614,-19.9586716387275));
#452=CARTESIAN_POINT('',(-9.83470808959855,1.82963226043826,-19.9178362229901));
#453=CARTESIAN_POINT('',(-9.7832771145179,2.08711188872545,-19.8924520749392));
#454=CARTESIAN_POINT('',(-9.6606617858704,2.59618182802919,-19.8324363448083));
#455=CARTESIAN_POINT('',(-9.58947940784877,2.84777272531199,-19.7978056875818));
#456=CARTESIAN_POINT('',(-9.42843099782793,3.34246836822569,-19.720303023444));
#457=CARTESIAN_POINT('',(-9.33863913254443,3.58560245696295,-19.6774637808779));
#458=CARTESIAN_POINT('',(-9.14105567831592,4.06298432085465,-19.5844658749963));
#459=CARTESIAN_POINT('',(-9.03326370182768,4.29723190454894,-19.5343070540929));
#460=CARTESIAN_POINT('',(-8.80063076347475,4.75551398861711,-19.4278257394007));
#461=CARTESIAN_POINT('',(-8.67579609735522,4.97955221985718,-19.371505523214));
#462=CARTESIAN_POINT('',(-8.40991307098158,5.41653080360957,-19.2538936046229));
#463=CARTESIAN_POINT('',(-8.2688583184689,5.62946673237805,-19.1925999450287));
#464=CARTESIAN_POINT('',(-7.96249543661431,6.0557115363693,-19.0625536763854));
#465=CARTESIAN_POINT('',(-7.7962377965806,6.2682689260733,-18.9935741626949));
#466=CARTESIAN_POINT('',(-7.4475548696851,6.67880739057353,-18.8531326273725));
#467=CARTESIAN_POINT('',(-7.26512865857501,6.87678763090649,-18.7816704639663));
#468=CARTESIAN_POINT('',(-6.88496142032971,7.25738906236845,-18.6379106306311));
#469=CARTESIAN_POINT('',(-6.68721091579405,7.44000060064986,-18.5656124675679));
#470=CARTESIAN_POINT('',(-6.27739804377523,7.7888836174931,-18.4219676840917));
#471=CARTESIAN_POINT('',(-6.06533299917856,7.95515202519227,-18.3506212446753));
#472=CARTESIAN_POINT('',(-5.61080680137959,8.2827111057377,-18.2052535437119));
#473=CARTESIAN_POINT('',(-5.3672646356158,8.44260565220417,-18.1314567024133));
#474=CARTESIAN_POINT('',(-4.8660415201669,8.74109142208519,-17.9894590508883));
#475=CARTESIAN_POINT('',(-4.60836662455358,8.87969167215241,-17.9212558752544));
#476=CARTESIAN_POINT('',(-4.08030079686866,9.13438777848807,-17.7927881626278));
#477=CARTESIAN_POINT('',(-3.8099137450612,9.25049044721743,-17.7325212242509));
#478=CARTESIAN_POINT('',(-3.25811404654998,9.45894522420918,-17.6222099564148));
#479=CARTESIAN_POINT('',(-2.97670262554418,9.55129996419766,-17.5721644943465));
#480=CARTESIAN_POINT('',(-2.42208495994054,9.70625458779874,-17.4870229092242));
#481=CARTESIAN_POINT('',(-2.14939374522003,9.77030307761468,-17.4512120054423));
#482=CARTESIAN_POINT('',(-1.59828353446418,9.87543221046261,-17.3919377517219));
#483=CARTESIAN_POINT('',(-1.31986478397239,9.91651383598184,-17.368473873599));
#484=CARTESIAN_POINT('',(-0.7599854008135,9.97504777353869,-17.3349233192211));
#485=CARTESIAN_POINT('',(-0.478527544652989,9.99252007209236,-17.3248253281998));
#486=CARTESIAN_POINT('',(0.0850025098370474,10.0036080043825,-17.3184259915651));
#487=CARTESIAN_POINT('',(0.367074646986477,9.99722591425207,-17.3221233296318));
#488=CARTESIAN_POINT('',(0.895404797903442,9.96291632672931,-17.3418743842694));
#489=CARTESIAN_POINT('',(1.14190017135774,9.93766509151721,-17.3563927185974));
#490=CARTESIAN_POINT('',(1.63163922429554,9.8690882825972,-17.3954780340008));
#491=CARTESIAN_POINT('',(1.8748818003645,9.82575672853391,-17.4200483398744));
#492=CARTESIAN_POINT('',(2.35639172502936,9.72152759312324,-17.4784283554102));
#493=CARTESIAN_POINT('',(2.59465974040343,9.66063238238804,-17.5122368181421));
#494=CARTESIAN_POINT('',(3.06495356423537,9.5218798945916,-17.5880654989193));
#495=CARTESIAN_POINT('',(3.29697683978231,9.44401584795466,-17.6300889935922));
#496=CARTESIAN_POINT('',(3.75871059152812,9.27007793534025,-17.7221768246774));
#497=CARTESIAN_POINT('',(3.98824705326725,9.17362860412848,-17.7724029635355));
#498=CARTESIAN_POINT('',(4.43843816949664,8.96447979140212,-17.878810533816));
#499=CARTESIAN_POINT('',(4.65908984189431,8.85177491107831,-17.9349939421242));
#500=CARTESIAN_POINT('',(5.09056177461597,8.61087933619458,-18.0518884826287));
#501=CARTESIAN_POINT('',(5.30138026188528,8.48268586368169,-18.1126004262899));
#502=CARTESIAN_POINT('',(5.71235236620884,8.21155546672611,-18.2371218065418));
#503=CARTESIAN_POINT('',(5.9125053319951,8.06861764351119,-18.3009314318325));
#504=CARTESIAN_POINT('',(6.32613167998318,7.74962298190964,-18.4384710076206));
#505=CARTESIAN_POINT('',(6.53806610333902,7.57166567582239,-18.5124312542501));
#506=CARTESIAN_POINT('',(6.9463748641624,7.19890817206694,-18.6605447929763));
#507=CARTESIAN_POINT('',(7.14275307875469,7.00411219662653,-18.7346980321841));
#508=CARTESIAN_POINT('',(7.51914658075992,6.5984132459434,-18.8814062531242));
#509=CARTESIAN_POINT('',(7.69914815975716,6.38749704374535,-18.9539598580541));
#510=CARTESIAN_POINT('',(8.04145286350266,5.95079617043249,-19.0955673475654));
#511=CARTESIAN_POINT('',(8.20376295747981,5.72501741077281,-19.164622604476));
#512=CARTESIAN_POINT('',(8.51679586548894,5.24872768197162,-19.3006480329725));
#513=CARTESIAN_POINT('',(8.66662084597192,4.99755374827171,-19.3673693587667));
#514=CARTESIAN_POINT('',(8.94436923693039,4.48152997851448,-19.4932401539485));
#515=CARTESIAN_POINT('',(9.07229162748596,4.21667950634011,-19.5523892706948));
#516=CARTESIAN_POINT('',(9.30479430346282,3.67526022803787,-19.6613492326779));
#517=CARTESIAN_POINT('',(9.40938943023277,3.39869900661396,-19.7111660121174));
#518=CARTESIAN_POINT('',(9.59405077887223,2.83582264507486,-19.7999810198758));
#519=CARTESIAN_POINT('',(9.6741198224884,2.54950863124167,-19.8389804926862));
#520=CARTESIAN_POINT('',(9.80306586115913,1.9936008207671,-19.9021913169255));
#521=CARTESIAN_POINT('',(9.85397724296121,1.72458658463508,-19.9273600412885));
#522=CARTESIAN_POINT('',(9.93361515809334,1.18250594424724,-19.9668602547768));
#523=CARTESIAN_POINT('',(9.96234289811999,0.909439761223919,-19.9811923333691));
#524=CARTESIAN_POINT('',(9.99722632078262,0.361621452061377,-19.9986076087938));
#525=CARTESIAN_POINT('',(10.0033910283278,0.0868700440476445,-20.0016953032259));
#526=CARTESIAN_POINT('',(9.99308881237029,-0.462095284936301,-19.996544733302));
#527=CARTESIAN_POINT('',(9.97662289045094,-0.736309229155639,-19.9883069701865));
#528=CARTESIAN_POINT('',(9.92343793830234,-1.26069578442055,-19.9618171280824));
#529=CARTESIAN_POINT('',(9.88839042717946,-1.51108216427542,-19.9443921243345));
#530=CARTESIAN_POINT('',(9.79963000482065,-2.0077033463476,-19.9005341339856));
#531=CARTESIAN_POINT('',(9.74591829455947,-2.25393841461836,-19.8741017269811));
#532=CARTESIAN_POINT('',(9.62038600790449,-2.7406844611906,-19.812845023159));
#533=CARTESIAN_POINT('',(9.54856442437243,-2.98119512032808,-19.7780202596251));
#534=CARTESIAN_POINT('',(9.38750534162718,-3.4550508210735,-19.7007681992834));
#535=CARTESIAN_POINT('',(9.29826711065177,-3.68839556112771,-19.6583405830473));
#536=CARTESIAN_POINT('',(9.1003752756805,-4.15316088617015,-19.5655046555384));
#537=CARTESIAN_POINT('',(8.99124296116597,-4.38433936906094,-19.5149041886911));
#538=CARTESIAN_POINT('',(8.75625210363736,-4.83663774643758,-19.4077573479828));
#539=CARTESIAN_POINT('',(8.63038758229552,-5.05775400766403,-19.3512088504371));
#540=CARTESIAN_POINT('',(8.22905651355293,-5.70436813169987,-19.1744474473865));
#541=CARTESIAN_POINT('',(7.92974633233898,-6.11337858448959,-19.0470672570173));
#542=CARTESIAN_POINT('',(7.24229945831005,-6.91779518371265,-18.7707873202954));
#543=CARTESIAN_POINT('',(6.84832629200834,-7.30792110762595,-18.6210027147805));
#544=CARTESIAN_POINT('',(6.21273944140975,-7.84082560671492,-18.3999640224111));
#545=CARTESIAN_POINT('',(5.99326478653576,-8.00984942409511,-18.3268393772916));
#546=CARTESIAN_POINT('',(5.54026055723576,-8.32960568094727,-18.183737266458));
#547=CARTESIAN_POINT('',(5.30672896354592,-8.4803354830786,-18.1137602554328));
#548=CARTESIAN_POINT('',(4.81507400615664,-8.76928163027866,-17.9757225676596));
#549=CARTESIAN_POINT('',(4.55630669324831,-8.90652817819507,-17.9079221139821));
#550=CARTESIAN_POINT('',(4.02618845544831,-9.15837639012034,-17.7804404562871));
#551=CARTESIAN_POINT('',(3.75484365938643,-9.27298894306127,-17.7207553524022));
#552=CARTESIAN_POINT('',(3.20145013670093,-9.47827705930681,-17.6118078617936));
#553=CARTESIAN_POINT('',(2.91941021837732,-9.56897185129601,-17.5625371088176));
#554=CARTESIAN_POINT('',(2.34661678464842,-9.72530086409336,-17.4764560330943));
#555=CARTESIAN_POINT('',(2.0558646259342,-9.79093896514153,-17.4396437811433));
#556=CARTESIAN_POINT('',(1.49647520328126,-9.89107565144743,-17.3830260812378));
#557=CARTESIAN_POINT('',(1.22839424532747,-9.92795857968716,-17.3619273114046));
#558=CARTESIAN_POINT('',(0.689439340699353,-9.97987692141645,-17.332136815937));
#559=CARTESIAN_POINT('',(0.418565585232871,-9.99491382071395,-17.3234442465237));
#560=CARTESIAN_POINT('',(-0.123513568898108,-10.0029096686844,-17.3188284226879));
#561=CARTESIAN_POINT('',(-0.394718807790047,-9.9958767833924,-17.3229004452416));
#562=CARTESIAN_POINT('',(-0.935172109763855,-9.95985898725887,-17.3436339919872));
#563=CARTESIAN_POINT('',(-1.20442025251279,-9.93087497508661,-17.3602950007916));
#564=CARTESIAN_POINT('',(-1.71311444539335,-9.85519722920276,-17.4033551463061));
#565=CARTESIAN_POINT('',(-1.95294800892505,-9.81046230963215,-17.4286705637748));
#566=CARTESIAN_POINT('',(-2.42772919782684,-9.70388285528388,-17.4882355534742));
#567=CARTESIAN_POINT('',(-2.66267517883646,-9.6420326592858,-17.5224880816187));
#568=CARTESIAN_POINT('',(-3.12622361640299,-9.50186064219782,-17.5988921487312));
#569=CARTESIAN_POINT('',(-3.35482710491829,-9.42354151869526,-17.6410423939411));
#570=CARTESIAN_POINT('',(-3.80469848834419,-9.25107208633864,-17.7320944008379));
#571=CARTESIAN_POINT('',(-4.02596303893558,-9.15691467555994,-17.7809991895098));
#572=CARTESIAN_POINT('',(-4.47462589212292,-8.94668289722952,-17.8877520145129));
#573=CARTESIAN_POINT('',(-4.70144417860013,-8.82956366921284,-17.9459794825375));
#574=CARTESIAN_POINT('',(-5.14454543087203,-8.57895403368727,-18.067122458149));
#575=CARTESIAN_POINT('',(-5.36082745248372,-8.44546216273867,-18.130038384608));
#576=CARTESIAN_POINT('',(-5.78205137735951,-8.16285657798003,-18.2590224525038));
#577=CARTESIAN_POINT('',(-5.98698926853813,-8.0137373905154,-18.3250916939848));
#578=CARTESIAN_POINT('',(-6.38466859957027,-7.70065351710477,-18.4588439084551));
#579=CARTESIAN_POINT('',(-6.57740828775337,-7.53668670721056,-18.5265271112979));
#580=CARTESIAN_POINT('',(-6.9725890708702,-7.17380336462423,-18.6702735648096));
#581=CARTESIAN_POINT('',(-7.17335317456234,-6.97306234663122,-18.746353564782));
#582=CARTESIAN_POINT('',(-7.55735140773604,-6.55492133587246,-18.8966226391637));
#583=CARTESIAN_POINT('',(-7.74059048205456,-6.33752607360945,-18.9708122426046));
#584=CARTESIAN_POINT('',(-8.08857822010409,-5.88693376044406,-19.1154396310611));
#585=CARTESIAN_POINT('',(-8.25331243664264,-5.65372458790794,-19.1858744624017));
#586=CARTESIAN_POINT('',(-8.56287912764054,-5.1728954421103,-19.3210638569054));
#587=CARTESIAN_POINT('',(-8.70771274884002,-4.92527630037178,-19.3858187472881));
#588=CARTESIAN_POINT('',(-8.97718827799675,-4.41518835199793,-19.5083417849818));
#589=CARTESIAN_POINT('',(-9.10167533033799,-4.15262447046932,-19.5660555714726));
#590=CARTESIAN_POINT('',(-9.32784736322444,-3.61607511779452,-19.6722841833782));
#591=CARTESIAN_POINT('',(-9.42953513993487,-3.34209105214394,-19.7208001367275));
#592=CARTESIAN_POINT('',(-9.60868749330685,-2.78539452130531,-19.8070877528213));
#593=CARTESIAN_POINT('',(-9.68620928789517,-2.50270444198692,-19.8448847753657));
#594=CARTESIAN_POINT('',(-9.81627609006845,-1.93047321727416,-19.908692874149));
#595=CARTESIAN_POINT('',(-9.86883635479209,-1.64093637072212,-19.9347111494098));
#596=CARTESIAN_POINT('',(-9.93894890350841,-1.12608352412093,-19.9695276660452));
#597=CARTESIAN_POINT('',(-9.96182346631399,-0.901651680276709,-19.9809348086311));
#598=CARTESIAN_POINT('',(-9.99234959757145,-0.451484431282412,-19.9961714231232));
#599=CARTESIAN_POINT('',(-10.0000007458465,-0.225748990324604,-20.0000006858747));
#600=CARTESIAN_POINT('',(-10.,0.,-20.));
#601=B_SPLINE_CURVE_WITH_KNOTS('',3,(#447,#448,#449,#450,#451,#452,#453,#454,#455,#456,#457,
#458,#459,#460,#461,#462,#463,#464,#465,#466,#467,#468,#469,#470,#471,#472,#473,#474,#475,#476,
#477,#478,#479,#480,#481,#482,#483,#484,#485,#486,#487,#488,#489,#490,#491,#492,#493,#494,#495,
#496,#497,#498,#499,#500,#501,#502,#503,#504,#505,#506,#507,#508,#509,#510,#511,#512,#513,#514,
#515,#516,#517,#518,#519,#520,#521,#522,#523,#524,#525,#526,#527,#528,#529,#530,#531,#532,#533,
#534,#535,#536,#537,#538,#539,#540,#541,#542,#543,#544,#545,#546,#547,#548,#549,#550,#551,#552,
#553,#554,#555,#556,#557,#558,#559,#560,#561,#562,#563,#564,#565,#566,#567,#568,#569,#570,#571,
#572,#573,#574,#575,#576,#577,#578,#579,#580,#581,#582,#583,#584,#585,#586,#587,#588,#589,#590,
#591,#592,#593,#594,#595,#596,#597,#598,#599,#600),.UNSPECIFIED.,.T.,.F.,(4,2,2,2,2,2,2,2,2,2,2,
2,2,2,2,2,2,2,2,2,2,2,2,2,2,2,2,2,2,2,2,2,2,2,2,2,2,2,2,2,2,2,2,2,2,2,2,2,2,2,2,2,2,2,2,2,2,2,2,
2,2,2,2,2,2,2,2,2,2,2,2,2,2,2,2,2,4),(0.,0.788710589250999,1.57776436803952,2.36814706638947,
3.15845073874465,3.94566328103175,4.73289277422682,5.51983223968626,6.30708290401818,
7.14179607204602,7.9765569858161,8.81183834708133,9.64727635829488,10.5477781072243,
11.447897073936,12.3477430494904,13.2474892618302,14.0934532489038,14.9393810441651,
15.7845922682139,16.6297228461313,17.3734776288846,18.1174786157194,18.8613792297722,
19.6055771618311,20.3667813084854,21.1282388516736,21.889833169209,22.6514739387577,
23.509891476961,24.3680943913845,25.2270091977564,26.0855844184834,26.9843425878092,
27.8831425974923,28.781369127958,29.6794922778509,30.5032194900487,31.3269018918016,
32.1502547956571,32.9735712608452,33.7329722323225,34.4923243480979,35.2517187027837,
36.0111449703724,36.7921013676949,37.5733375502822,39.1349970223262,40.850013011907,
41.7087612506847,42.5676331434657,43.4684238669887,44.3687801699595,45.2684104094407,
46.167901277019,46.9810473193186,47.7941380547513,48.6069279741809,49.4196846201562,
50.1547113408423,50.889981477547,51.6251312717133,52.3606115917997,53.1452977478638,
53.9300540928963,54.7150862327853,55.5002308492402,56.3809909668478,57.2615018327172,
58.1426954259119,59.0238382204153,59.9114030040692,60.7988588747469,61.6841972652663,
62.5689938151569,63.2460309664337,63.9230868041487),.UNSPECIFIED.);
#602=CARTESIAN_POINT('',(-10.,0.,-20.));
#603=VERTEX_POINT('',#602);
#604=EDGE_CURVE('E40',#603,#603,#601,.T.);
#605=ORIENTED_EDGE('',*,*,#604,.T.);
#606=EDGE_LOOP('',(#605));
#607=FACE_BOUND('',#606,.T.);
#608=CARTESIAN_POINT('',(10.,0.,20.));
#609=CARTESIAN_POINT('',(9.99999913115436,0.26297774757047,19.9999992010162));
#610=CARTESIAN_POINT('',(9.98961448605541,0.525973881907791,19.9948010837));
#611=CARTESIAN_POINT('',(9.94819417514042,1.05002923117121,19.9741395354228));
#612=CARTESIAN_POINT('',(9.91714952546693,1.31108755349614,19.9586716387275));
#613=CARTESIAN_POINT('',(9.83470808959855,1.82963226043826,19.9178362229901));
#614=CARTESIAN_POINT('',(9.7832771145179,2.08711188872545,19.8924520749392));
#615=CARTESIAN_POINT('',(9.6606617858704,2.59618182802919,19.8324363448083));
#616=CARTESIAN_POINT('',(9.58947940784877,2.84777272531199,19.7978056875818));
#617=CARTESIAN_POINT('',(9.42843099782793,3.34246836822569,19.720303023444));
#618=CARTESIAN_POINT('',(9.33863913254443,3.58560245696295,19.6774637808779));
#619=CARTESIAN_POINT('',(9.14105567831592,4.06298432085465,19.5844658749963));
#620=CARTESIAN_POINT('',(9.03326370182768,4.29723190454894,19.5343070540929));
#621=CARTESIAN_POINT('',(8.80063076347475,4.75551398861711,19.4278257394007));
#622=CARTESIAN_POINT('',(8.67579609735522,4.97955221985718,19.371505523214));
#623=CARTESIAN_POINT('',(8.40991307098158,5.41653080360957,19.2538936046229));
#624=CARTESIAN_POINT('',(8.2688583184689,5.62946673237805,19.1925999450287));
#625=CARTESIAN_POINT('',(7.96249543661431,6.0557115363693,19.0625536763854));
#626=CARTESIAN_POINT('',(7.7962377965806,6.2682689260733,18.9935741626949));
#627=CARTESIAN_POINT('',(7.4475548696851,6.67880739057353,18.8531326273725));
#628=CARTESIAN_POINT('',(7.26512865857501,6.87678763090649,18.7816704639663));
#629=CARTESIAN_POINT('',(6.88496142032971,7.25738906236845,18.6379106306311));
#630=CARTESIAN_POINT('',(6.68721091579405,7.44000060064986,18.5656124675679));
#631=CARTESIAN_POINT('',(6.27739804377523,7.7888836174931,18.4219676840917));
#632=CARTESIAN_POINT('',(6.06533299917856,7.95515202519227,18.3506212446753));
#633=CARTESIAN_POINT('',(5.61080680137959,8.2827111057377,18.2052535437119));
#634=CARTESIAN_POINT('',(5.3672646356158,8.44260565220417,18.1314567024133));
#635=CARTESIAN_POINT('',(4.8660415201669,8.74109142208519,17.9894590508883));
#636=CARTESIAN_POINT('',(4.60836662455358,8.87969167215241,17.9212558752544));
#637=CARTESIAN_POINT('',(4.08030079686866,9.13438777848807,17.7927881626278));
#638=CARTESIAN_POINT('',(3.8099137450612,9.25049044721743,17.7325212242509));
#639=CARTESIAN_POINT('',(3.25811404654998,9.45894522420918,17.6222099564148));
#640=CARTESIAN_POINT('',(2.97670262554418,9.55129996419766,17.5721644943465));
#641=CARTESIAN_POINT('',(2.42208495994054,9.70625458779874,17.4870229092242));
#642=CARTESIAN_POINT('',(2.14939374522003,9.77030307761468,17.4512120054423));
#643=CARTESIAN_POINT('',(1.59828353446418,9.87543221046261,17.3919377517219));
#644=CARTESIAN_POINT('',(1.31986478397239,9.91651383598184,17.368473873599));
#645=CARTESIAN_POINT('',(0.7599854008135,9.97504777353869,17.3349233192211));
#646=CARTESIAN_POINT('',(0.478527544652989,9.99252007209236,17.3248253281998));
#647=CARTESIAN_POINT('',(-0.0850025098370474,10.0036080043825,17.3184259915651));
#648=CARTESIAN_POINT('',(-0.367074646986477,9.99722591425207,17.3221233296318));
#649=CARTESIAN_POINT('',(-0.895404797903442,9.96291632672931,17.3418743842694));
#650=CARTESIAN_POINT('',(-1.14190017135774,9.93766509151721,17.3563927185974));
#651=CARTESIAN_POINT('',(-1.63163922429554,9.8690882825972,17.3954780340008));
#652=CARTESIAN_POINT('',(-1.8748818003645,9.82575672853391,17.4200483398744));
#653=CARTESIAN_POINT('',(-2.35639172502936,9.72152759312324,17.4784283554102));
#654=CARTESIAN_POINT('',(-2.59465974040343,9.66063238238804,17.5122368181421));
#655=CARTESIAN_POINT('',(-3.06495356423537,9.5218798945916,17.5880654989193));
#656=CARTESIAN_POINT('',(-3.29697683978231,9.44401584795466,17.6300889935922));
#657=CARTESIAN_POINT('',(-3.75871059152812,9.27007793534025,17.7221768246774));
#658=CARTESIAN_POINT('',(-3.98824705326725,9.17362860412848,17.7724029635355));
#659=CARTESIAN_POINT('',(-4.43843816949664,8.96447979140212,17.878810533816));
#660=CARTESIAN_POINT('',(-4.65908984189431,8.85177491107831,17.9349939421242));
#661=CARTESIAN_POINT('',(-5.09056177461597,8.61087933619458,18.0518884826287));
#662=CARTESIAN_POINT('',(-5.30138026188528,8.48268586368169,18.1126004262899));
#663=CARTESIAN_POINT('',(-5.71235236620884,8.21155546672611,18.2371218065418));
#664=CARTESIAN_POINT('',(-5.9125053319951,8.06861764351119,18.3009314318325));
#665=CARTESIAN_POINT('',(-6.32613167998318,7.74962298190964,18.4384710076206));
#666=CARTESIAN_POINT('',(-6.53806610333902,7.57166567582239,18.5124312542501));
#667=CARTESIAN_POINT('',(-6.9463748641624,7.19890817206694,18.6605447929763));
#668=CARTESIAN_POINT('',(-7.14275307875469,7.00411219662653,18.7346980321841));
#669=CARTESIAN_POINT('',(-7.51914658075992,6.5984132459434,18.8814062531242));
#670=CARTESIAN_POINT('',(-7.69914815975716,6.38749704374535,18.9539598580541));
#671=CARTESIAN_POINT('',(-8.04145286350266,5.95079617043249,19.0955673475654));
#672=CARTESIAN_POINT('',(-8.20376295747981,5.72501741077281,19.164622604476));
#673=CARTESIAN_POINT('',(-8.51679586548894,5.24872768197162,19.3006480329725));
#674=CARTESIAN_POINT('',(-8.66662084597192,4.99755374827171,19.3673693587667));
#675=CARTESIAN_POINT('',(-8.94436923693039,4.48152997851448,19.4932401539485));
#676=CARTESIAN_POINT('',(-9.07229162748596,4.21667950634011,19.5523892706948));
#677=CARTESIAN_POINT('',(-9.30479430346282,3.67526022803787,19.6613492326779));
#678=CARTESIAN_POINT('',(-9.40938943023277,3.39869900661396,19.7111660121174));
#679=CARTESIAN_POINT('',(-9.59405077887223,2.83582264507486,19.7999810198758));
#680=CARTESIAN_POINT('',(-9.6741198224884,2.54950863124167,19.8389804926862));
#681=CARTESIAN_POINT('',(-9.80306586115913,1.9936008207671,19.9021913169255));
#682=CARTESIAN_POINT('',(-9.85397724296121,1.72458658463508,19.9273600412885));
#683=CARTESIAN_POINT('',(-9.93361515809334,1.18250594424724,19.9668602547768));
#684=CARTESIAN_POINT('',(-9.96234289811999,0.909439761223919,19.9811923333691));
#685=CARTESIAN_POINT('',(-9.99722632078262,0.361621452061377,19.9986076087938));
#686=CARTESIAN_POINT('',(-10.0033910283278,0.0868700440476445,20.0016953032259));
#687=CARTESIAN_POINT('',(-9.99308881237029,-0.462095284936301,19.996544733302));
#688=CARTESIAN_POINT('',(-9.97662289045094,-0.736309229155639,19.9883069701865));
#689=CARTESIAN_POINT('',(-9.92343793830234,-1.26069578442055,19.9618171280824));
#690=CARTESIAN_POINT('',(-9.88839042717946,-1.51108216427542,19.9443921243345));
#691=CARTESIAN_POINT('',(-9.79963000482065,-2.0077033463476,19.9005341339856));
#692=CARTESIAN_POINT('',(-9.74591829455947,-2.25393841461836,19.8741017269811));
#693=CARTESIAN_POINT('',(-9.62038600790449,-2.7406844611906,19.812845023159));
#694=CARTESIAN_POINT('',(-9.54856442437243,-2.98119512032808,19.7780202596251));
#695=CARTESIAN_POINT('',(-9.38750534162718,-3.4550508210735,19.7007681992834));
#696=CARTESIAN_POINT('',(-9.29826711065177,-3.68839556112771,19.6583405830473));
#697=CARTESIAN_POINT('',(-9.1003752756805,-4.15316088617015,19.5655046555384));
#698=CARTESIAN_POINT('',(-8.99124296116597,-4.38433936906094,19.5149041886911));
#699=CARTESIAN_POINT('',(-8.75625210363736,-4.83663774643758,19.4077573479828));
#700=CARTESIAN_POINT('',(-8.63038758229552,-5.05775400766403,19.3512088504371));
#701=CARTESIAN_POINT('',(-8.22905651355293,-5.70436813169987,19.1744474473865));
#702=CARTESIAN_POINT('',(-7.92974633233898,-6.11337858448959,19.0470672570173));
#703=CARTESIAN_POINT('',(-7.24229945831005,-6.91779518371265,18.7707873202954));
#704=CARTESIAN_POINT('',(-6.84832629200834,-7.30792110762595,18.6210027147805));
#705=CARTESIAN_POINT('',(-6.21273944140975,-7.84082560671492,18.3999640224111));
#706=CARTESIAN_POINT('',(-5.99326478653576,-8.00984942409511,18.3268393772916));
#707=CARTESIAN_POINT('',(-5.54026055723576,-8.32960568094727,18.183737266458));
#708=CARTESIAN_POINT('',(-5.30672896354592,-8.4803354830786,18.1137602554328));
#709=CARTESIAN_POINT('',(-4.81507400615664,-8.76928163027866,17.9757225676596));
#710=CARTESIAN_POINT('',(-4.55630669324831,-8.90652817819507,17.9079221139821));
#711=CARTESIAN_POINT('',(-4.02618845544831,-9.15837639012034,17.7804404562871));
#712=CARTESIAN_POINT('',(-3.75484365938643,-9.27298894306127,17.7207553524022));
#713=CARTESIAN_POINT('',(-3.20145013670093,-9.47827705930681,17.6118078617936));
#714=CARTESIAN_POINT('',(-2.91941021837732,-9.56897185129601,17.5625371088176));
#715=CARTESIAN_POINT('',(-2.34661678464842,-9.72530086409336,17.4764560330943));
#716=CARTESIAN_POINT('',(-2.0558646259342,-9.79093896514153,17.4396437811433));
#717=CARTESIAN_POINT('',(-1.49647520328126,-9.89107565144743,17.3830260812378));
#718=CARTESIAN_POINT('',(-1.22839424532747,-9.92795857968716,17.3619273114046));
#719=CARTESIAN_POINT('',(-0.689439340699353,-9.97987692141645,17.332136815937));
#720=CARTESIAN_POINT('',(-0.418565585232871,-9.99491382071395,17.3234442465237));
#721=CARTESIAN_POINT('',(0.123513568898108,-10.0029096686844,17.3188284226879));
#722=CARTESIAN_POINT('',(0.394718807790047,-9.9958767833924,17.3229004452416));
#723=CARTESIAN_POINT('',(0.935172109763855,-9.95985898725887,17.3436339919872));
#724=CARTESIAN_POINT('',(1.20442025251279,-9.93087497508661,17.3602950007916));
#725=CARTESIAN_POINT('',(1.71311444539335,-9.85519722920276,17.4033551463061));
#726=CARTESIAN_POINT('',(1.95294800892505,-9.81046230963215,17.4286705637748));
#727=CARTESIAN_POINT('',(2.42772919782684,-9.70388285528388,17.4882355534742));
#728=CARTESIAN_POINT('',(2.66267517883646,-9.6420326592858,17.5224880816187));
#729=CARTESIAN_POINT('',(3.12622361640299,-9.50186064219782,17.5988921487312));
#730=CARTESIAN_POINT('',(3.35482710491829,-9.42354151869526,17.6410423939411));
#731=CARTESIAN_POINT('',(3.80469848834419,-9.25107208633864,17.7320944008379));
#732=CARTESIAN_POINT('',(4.02596303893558,-9.15691467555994,17.7809991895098));
#733=CARTESIAN_POINT('',(4.47462589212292,-8.94668289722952,17.8877520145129));
#734=CARTESIAN_POINT('',(4.70144417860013,-8.82956366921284,17.9459794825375));
#735=CARTESIAN_POINT('',(5.14454543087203,-8.57895403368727,18.067122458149));
#736=CARTESIAN_POINT('',(5.36082745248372,-8.44546216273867,18.130038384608));
#737=CARTESIAN_POINT('',(5.78205137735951,-8.16285657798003,18.2590224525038));
#738=CARTESIAN_POINT('',(5.98698926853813,-8.0137373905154,18.3250916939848));
#739=CARTESIAN_POINT('',(6.38466859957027,-7.70065351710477,18.4588439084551));
#740=CARTESIAN_POINT('',(6.57740828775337,-7.53668670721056,18.5265271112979));
#741=CARTESIAN_POINT('',(6.9725890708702,-7.17380336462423,18.6702735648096));
#742=CARTESIAN_POINT('',(7.17335317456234,-6.97306234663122,18.746353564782));
#743=CARTESIAN_POINT('',(7.55735140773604,-6.55492133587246,18.8966226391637));
#744=CARTESIAN_POINT('',(7.74059048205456,-6.33752607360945,18.9708122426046));
#745=CARTESIAN_POINT('',(8.08857822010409,-5.88693376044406,19.1154396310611));
#746=CARTESIAN_POINT('',(8.25331243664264,-5.65372458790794,19.1858744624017));
#747=CARTESIAN_POINT('',(8.56287912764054,-5.1728954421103,19.3210638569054));
#748=CARTESIAN_POINT('',(8.70771274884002,-4.92527630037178,19.3858187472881));
#749=CARTESIAN_POINT('',(8.97718827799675,-4.41518835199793,19.5083417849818));
#750=CARTESIAN_POINT('',(9.10167533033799,-4.15262447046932,19.5660555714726));
#751=CARTESIAN_POINT('',(9.32784736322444,-3.61607511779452,19.6722841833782));
#752=CARTESIAN_POINT('',(9.42953513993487,-3.34209105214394,19.7208001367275));
#753=CARTESIAN_POINT('',(9.60868749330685,-2.78539452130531,19.8070877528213));
#754=CARTESIAN_POINT('',(9.68620928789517,-2.50270444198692,19.8448847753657));
#755=CARTESIAN_POINT('',(9.81627609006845,-1.93047321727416,19.908692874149));
#756=CARTESIAN_POINT('',(9.86883635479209,-1.64093637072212,19.9347111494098));
#757=CARTESIAN_POINT('',(9.93894890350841,-1.12608352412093,19.9695276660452));
#758=CARTESIAN_POINT('',(9.96182346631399,-0.901651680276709,19.9809348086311));
#759=CARTESIAN_POINT('',(9.99234959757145,-0.451484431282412,19.9961714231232));
#760=CARTESIAN_POINT('',(10.0000007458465,-0.225748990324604,20.0000006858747));
#761=CARTESIAN_POINT('',(10.,0.,20.));
#762=B_SPLINE_CURVE_WITH_KNOTS('',3,(#608,#609,#610,#611,#612,#613,#614,#615,#616,#617,#618,
#619,#620,#621,#622,#623,#624,#625,#626,#627,#628,#629,#630,#631,#632,#633,#634,#635,#636,#637,
#638,#639,#640,#641,#642,#643,#644,#645,#646,#647,#648,#649,#650,#651,#652,#653,#654,#655,#656,
#657,#658,#659,#660,#661,#662,#663,#664,#665,#666,#667,#668,#669,#670,#671,#672,#673,#674,#675,
#676,#677,#678,#679,#680,#681,#682,#683,#684,#685,#686,#687,#688,#689,#690,#691,#692,#693,#694,
#695,#696,#697,#698,#699,#700,#701,#702,#703,#704,#705,#706,#707,#708,#709,#710,#711,#712,#713,
#714,#715,#716,#717,#718,#719,#720,#721,#722,#723,#724,#725,#726,#727,#728,#729,#730,#731,#732,
#733,#734,#735,#736,#737,#738,#739,#740,#741,#742,#743,#744,#745,#746,#747,#748,#749,#750,#751,
#752,#753,#754,#755,#756,#757,#758,#759,#760,#761),.UNSPECIFIED.,.T.,.F.,(4,2,2,2,2,2,2,2,2,2,2,
2,2,2,2,2,2,2,2,2,2,2,2,2,2,2,2,2,2,2,2,2,2,2,2,2,2,2,2,2,2,2,2,2,2,2,2,2,2,2,2,2,2,2,2,2,2,2,2,
2,2,2,2,2,2,2,2,2,2,2,2,2,2,2,2,2,4),(0.,0.788710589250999,1.57776436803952,2.36814706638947,
3.15845073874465,3.94566328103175,4.73289277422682,5.51983223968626,6.30708290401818,
7.14179607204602,7.9765569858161,8.81183834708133,9.64727635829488,10.5477781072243,
11.447897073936,12.3477430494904,13.2474892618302,14.0934532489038,14.9393810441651,
15.7845922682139,16.6297228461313,17.3734776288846,18.1174786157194,18.8613792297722,
19.6055771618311,20.3667813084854,21.1282388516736,21.889833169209,22.6514739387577,
23.509891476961,24.3680943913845,25.2270091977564,26.0855844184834,26.9843425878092,
27.8831425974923,28.781369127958,29.6794922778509,30.5032194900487,31.3269018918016,
32.1502547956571,32.9735712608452,33.7329722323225,34.4923243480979,35.2517187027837,
36.0111449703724,36.7921013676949,37.5733375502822,39.1349970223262,40.850013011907,
41.7087612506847,42.5676331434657,43.4684238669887,44.3687801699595,45.2684104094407,
46.167901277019,46.9810473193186,47.7941380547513,48.6069279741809,49.4196846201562,
50.1547113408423,50.889981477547,51.6251312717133,52.3606115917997,53.1452977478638,
53.9300540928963,54.7150862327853,55.5002308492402,56.3809909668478,57.2615018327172,
58.1426954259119,59.0238382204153,59.9114030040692,60.7988588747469,61.6841972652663,
62.5689938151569,63.2460309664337,63.9230868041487),.UNSPECIFIED.);
#763=CARTESIAN_POINT('',(10.,0.,20.));
#764=VERTEX_POINT('',#763);
#765=EDGE_CURVE('E78',#764,#764,#762,.T.);
#766=ORIENTED_EDGE('',*,*,#765,.T.);
#767=EDGE_LOOP('',(#766));
#768=FACE_BOUND('',#767,.T.);
#769=ORIENTED_EDGE('',*,*,#239,.T.);
#770=EDGE_LOOP('',(#769));
#771=FACE_BOUND('',#770,.T.);
#772=ORIENTED_EDGE('',*,*,#250,.T.);
#773=EDGE_LOOP('',(#772));
#774=FACE_BOUND('',#773,.T.);
#775=ORIENTED_EDGE('',*,*,#434,.F.);
#776=EDGE_LOOP('',(#775));
#777=FACE_BOUND('',#776,.T.);
#778=ORIENTED_EDGE('',*,*,#189,.F.);
#779=EDGE_LOOP('',(#778));
#780=FACE_BOUND('',#779,.T.);
#781=ADVANCED_FACE('F68',(#607,#768,#771,#774,#777,#780),#446,.F.);
#782=CARTESIAN_POINT('',(0.,0.,-48.));
#783=DIRECTION('',(0.,0.,1.));
#784=DIRECTION('',(1.,0.,0.));
#785=AXIS2_PLACEMENT_3D('',#782,#783,#784);
#786=CYLINDRICAL_SURFACE('',#785,10.);
#787=ORIENTED_EDGE('',*,*,#217,.T.);
#788=EDGE_LOOP('',(#787));
#789=FACE_BOUND('',#788,.T.);
#790=ORIENTED_EDGE('',*,*,#765,.F.);
#791=EDGE_LOOP('',(#790));
#792=FACE_BOUND('',#791,.T.);
#793=ADVANCED_FACE('F71',(#789,#792),#786,.F.);
#794=ORIENTED_EDGE('',*,*,#228,.T.);
#795=EDGE_LOOP('',(#794));
#796=FACE_BOUND('',#795,.T.);
#797=ORIENTED_EDGE('',*,*,#604,.F.);
#798=EDGE_LOOP('',(#797));
#799=FACE_BOUND('',#798,.T.);
#800=ADVANCED_FACE('F73',(#796,#799),#786,.F.);
#801=CLOSED_SHELL('',(#204,#268,#441,#781,#793,#800));
#802=MANIFOLD_SOLID_BREP('B2',#801);
#803=ADVANCED_BREP_SHAPE_REPRESENTATION('',(#18,#802),#14);
#804=SHAPE_DEFINITION_REPRESENTATION(#9,#803);
ENDSEC;
END-ISO-10303-21;
